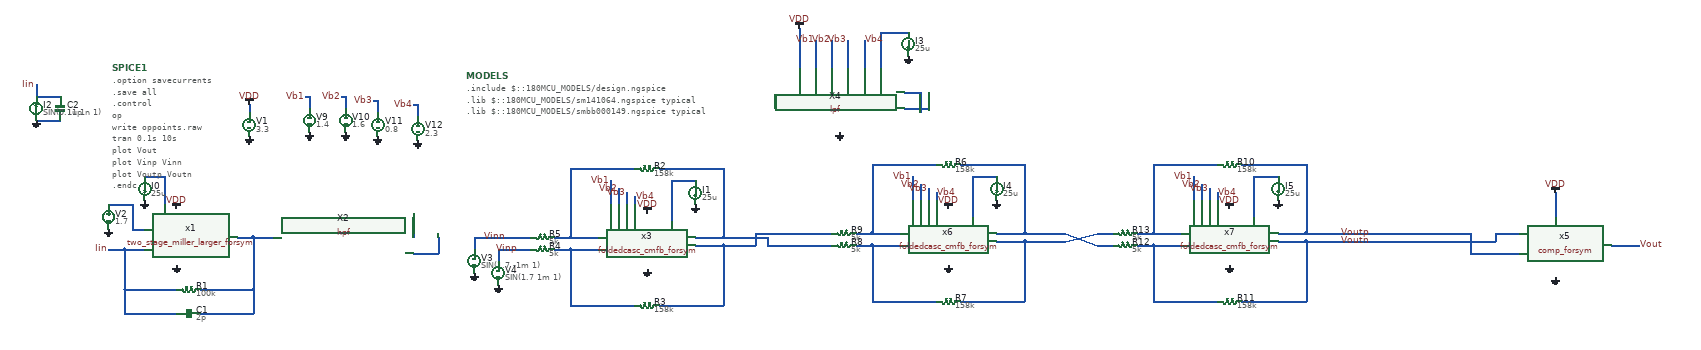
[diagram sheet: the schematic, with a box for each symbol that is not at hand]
v {xschem version=3.4.8RC file_version=1.3}
G {}
K {}
V {}
S {}
F {}
E {}
N -270 -240 -230 -240 {lab=#net1
spice_ignore=true}
N -500 -390 -450 -390 {lab=#net2
spice_ignore=true}
N -450 -390 -450 -320 {lab=#net2
spice_ignore=true}
N -230 -240 -230 -110 {lab=#net1
spice_ignore=true}
N -550 -210 -550 -110 {lab=Iin
spice_ignore=true}
N -550 -210 -500 -210 {lab=Iin
spice_ignore=true}
N -360 -110 -230 -110 {lab=#net1
spice_ignore=true}
N -550 -110 -420 -110 {lab=Iin
spice_ignore=true}
N -360 -50 -230 -50 {lab=#net1
spice_ignore=true}
N -230 -110 -230 -50 {lab=#net1
spice_ignore=true}
N -550 -50 -420 -50 {lab=Iin
spice_ignore=true}
N -550 -110 -550 -50 {lab=Iin
spice_ignore=true}
N -230 -240 -180 -240 {lab=#net1
spice_ignore=true}
N -590 -210 -550 -210 {lab=Iin
spice_ignore=true}
N -590 -320 -530 -320 {lab=#net3
spice_ignore=true}
N -530 -320 -530 -260 {lab=#net3
spice_ignore=true}
N -530 -260 -500 -260 {lab=#net3
spice_ignore=true}
N -240 -570 -240 -550 {lab=VDD}
N 870 -220 940 -220 {lab=#net1}
N 940 -220 940 -70 {lab=#net1}
N 560 -210 630 -210 {lab=#net2}
N 560 -240 630 -240 {lab=#net3}
N 560 -410 560 -260 {lab=#net3}
N 870 -240 940 -240 {lab=#net4}
N 940 -410 940 -240 {lab=#net4}
N 940 -240 1050 -240 {lab=#net4}
N 940 -220 1020 -220 {lab=#net1}
N 660 -380 660 -320 {lab=Vb1}
N 680 -360 680 -320 {lab=Vb2}
N 780 -410 940 -410 {lab=#net4}
N 560 -410 720 -410 {lab=#net3}
N 780 -70 940 -70 {lab=#net1}
N 560 -70 720 -70 {lab=#net2}
N 520 -240 560 -240 {lab=#net3}
N 520 -210 560 -210 {lab=#net2}
N 420 -210 460 -210 {lab=Vinp}
N 560 -260 560 -240 {lab=#net3}
N 560 -210 560 -70 {lab=#net2}
N 700 -350 700 -320 {lab=Vb3}
N 720 -340 720 -320 {lab=Vb4}
N 810 -380 810 -280 {lab=#net5}
N 810 -380 870 -380 {lab=#net5}
N -770 -620 -770 -590 {lab=Iin
spice_ignore=true}
N -770 -590 -710 -590 {lab=Iin
spice_ignore=true}
N -770 -530 -710 -530 {lab=0
spice_ignore=true}
N -90 -590 -90 -560 {lab=Vb1
}
N -100 -590 -90 -590 {lab=Vb1
}
N 0 -590 0 -560 {lab=Vb2
}
N -10 -590 0 -590 {lab=Vb2
}
N 80 -580 80 -550 {lab=Vb3
}
N 70 -580 80 -580 {lab=Vb3
}
N 180 -570 180 -540 {lab=Vb4
}
N 170 -570 180 -570 {lab=Vb4
}
N 1070 -580 1070 -560 {lab=#net6}
N 1130 -760 1130 -660 {lab=VDD}
N 1170 -730 1170 -660 {lab=Vb1}
N 1210 -730 1210 -660 {lab=Vb2}
N 1250 -730 1250 -660 {lab=Vb3}
N 1290 -730 1290 -660 {lab=Vb4}
N 1330 -750 1330 -660 {lab=#net7}
N 1330 -750 1400 -750 {lab=#net7}
N 170 -200 230 -200 {lab=#net13
spice_ignore=true}
N 230 -240 230 -200 {lab=#net13
spice_ignore=true}
N 170 -300 170 -240 {lab=#net14
spice_ignore=true}
N 420 -240 460 -240 {lab=Vinn}
N 320 -240 320 -210 {lab=Vinn
}
N 380 -210 380 -180 {lab=Vinp
}
N 380 -210 420 -210 {lab=Vinp}
N 320 -240 420 -240 {lab=Vinn}
N 3010 -350 3010 -290 {lab=VDD}
N 3150 -220 3220 -220 {lab=Vout}
N 1390 -560 1450 -560 {lab=#net8}
N 1450 -600 1450 -560 {lab=#net8}
N 2860 -250 2920 -250 {lab=Voutn}
N 1390 -600 1430 -600 {lab=#net9}
N 2840 -200 2920 -200 {lab=Voutp}
N 1430 -600 1430 -550 {lab=#net9}
N 2480 -250 2800 -250 {lab=Voutp}
N 2800 -250 2800 -200 {lab=Voutp}
N 2800 -200 2840 -200 {lab=Voutp}
N 2480 -230 2860 -230 {lab=Voutn}
N 2860 -250 2860 -230 {lab=Voutn}
N 1620 -230 1690 -230 {lab=#net10}
N 1690 -230 1690 -80 {lab=#net10}
N 1310 -220 1380 -220 {lab=#net11}
N 1310 -250 1380 -250 {lab=#net12}
N 1310 -420 1310 -270 {lab=#net12}
N 1620 -250 1690 -250 {lab=#net13}
N 1690 -420 1690 -250 {lab=#net13}
N 1690 -230 1770 -230 {lab=#net10}
N 1410 -390 1410 -330 {lab=Vb1}
N 1430 -370 1430 -330 {lab=Vb2}
N 1530 -420 1690 -420 {lab=#net13}
N 1310 -420 1470 -420 {lab=#net12}
N 1530 -80 1690 -80 {lab=#net10}
N 1310 -80 1470 -80 {lab=#net11}
N 1270 -250 1310 -250 {lab=#net12}
N 1270 -220 1310 -220 {lab=#net11}
N 1170 -220 1210 -220 {lab=#net4}
N 1310 -270 1310 -250 {lab=#net12}
N 1310 -220 1310 -80 {lab=#net11}
N 1450 -360 1450 -330 {lab=Vb3}
N 1470 -350 1470 -330 {lab=Vb4}
N 1560 -390 1560 -290 {lab=#net14}
N 1560 -390 1620 -390 {lab=#net14}
N 1170 -250 1210 -250 {lab=#net1}
N 1770 -230 1790 -230 {lab=#net10}
N 1690 -250 1790 -250 {lab=#net13}
N 1050 -240 1050 -220 {lab=#net4}
N 1050 -220 1170 -220 {lab=#net4}
N 1020 -250 1170 -250 {lab=#net1}
N 1020 -250 1020 -220 {lab=#net1}
N 2320 -230 2390 -230 {lab=Voutn}
N 2390 -230 2390 -80 {lab=Voutn}
N 2010 -220 2080 -220 {lab=#net15}
N 2010 -250 2080 -250 {lab=#net16}
N 2010 -420 2010 -270 {lab=#net16}
N 2320 -250 2390 -250 {lab=Voutp}
N 2390 -420 2390 -250 {lab=Voutp}
N 2390 -230 2470 -230 {lab=Voutn}
N 2110 -390 2110 -330 {lab=Vb1}
N 2130 -370 2130 -330 {lab=Vb2}
N 2230 -420 2390 -420 {lab=Voutp}
N 2010 -420 2170 -420 {lab=#net16}
N 2230 -80 2390 -80 {lab=Voutn}
N 2010 -80 2170 -80 {lab=#net15}
N 1970 -250 2010 -250 {lab=#net16}
N 1970 -220 2010 -220 {lab=#net15}
N 1870 -220 1910 -220 {lab=#net13}
N 2010 -270 2010 -250 {lab=#net16}
N 2010 -220 2010 -80 {lab=#net15}
N 2150 -360 2150 -330 {lab=Vb3}
N 2170 -350 2170 -330 {lab=Vb4}
N 2260 -390 2260 -290 {lab=#net17}
N 2260 -390 2320 -390 {lab=#net17}
N 1870 -250 1910 -250 {lab=#net10}
N 1790 -250 1870 -220 {lab=#net13}
N 1790 -230 1870 -250 {lab=#net10}
N 2390 -250 2480 -250 {lab=Voutp}
N 2470 -230 2480 -230 {lab=Voutn}
C {isource.sym} -500 -360 0 0 {name=I0 value=25u
spice_ignore=true}
C {gnd.sym} -500 -330 0 0 {name=l1 lab=0
spice_ignore=true}
C {vdd.sym} -420 -310 0 0 {name=l3 lab=VDD
spice_ignore=true}
C {gnd.sym} -420 -170 0 0 {name=l4 lab=0
spice_ignore=true}
C {vsource.sym} -240 -520 0 0 {name=V1 value=3.3 savecurrent=false}
C {vdd.sym} -240 -570 0 0 {name=l2 lab=VDD}
C {gnd.sym} -240 -490 0 0 {name=l11 lab=0}
C {lab_pin.sym} -590 -210 0 0 {name=p1 sig_type=std_logic lab=Iin
spice_ignore=true}
C {res.sym} -390 -110 1 0 {name=R1
value=100k
footprint=1206
device=resistor
m=1
spice_ignore=true}
C {capa.sym} -390 -50 1 0 {name=C1
m=1
value=2p
footprint=1206
device="ceramic capacitor"
spice_ignore=true}
C {gnd.sym} -590 -260 0 0 {name=l5 lab=0
spice_ignore=true}
C {vsource.sym} -590 -290 0 0 {name=V2 value=1.7 savecurrent=false
spice_ignore=true}
C {chipathon-2026-ppg/jz_tia/two_stage_miller_larger_forsym.sym} -420 -240 0 0 {name=x1
spice_ignore=true}
C {chipathon-2026-ppg/ps-filters/hpf.sym} 10 -220 0 0 {name=X2
spice_ignore=true}
C {lab_pin.sym} 680 -360 3 1 {name=p2 sig_type=std_logic lab=Vb2
}
C {lab_pin.sym} 660 -380 0 0 {name=p4 sig_type=std_logic lab=Vb1
}
C {vdd.sym} 750 -300 0 0 {name=l7 lab=VDD}
C {isource.sym} 870 -350 0 0 {name=I1 value=25u
}
C {gnd.sym} 750 -160 0 0 {name=l8 lab=0
}
C {res.sym} 750 -410 1 0 {name=R2
value=158k
footprint=1206
device=resistor
m=1}
C {res.sym} 750 -70 1 0 {name=R3
value=158k
footprint=1206
device=resistor
m=1}
C {res.sym} 490 -210 1 0 {name=R4
value=5k
footprint=1206
device=resistor
m=1}
C {res.sym} 490 -240 1 0 {name=R5
value=5k
footprint=1206
device=resistor
m=1}
C {chipathon-2026-ppg/jz_fda2/foldedcasc_cmfb_forsym.sym} 760 -30 0 0 {name=x3}
C {lab_pin.sym} 720 -340 0 1 {name=p7 sig_type=std_logic lab=Vb4
}
C {lab_pin.sym} 700 -350 3 1 {name=p8 sig_type=std_logic lab=Vb3
}
C {gnd.sym} 870 -320 0 0 {name=l9 lab=0
}
C {chipathon-2026-ppg/ps-filters/lpf.sym} 1230 -580 0 0 {name=X4}
C {gnd.sym} -770 -530 0 0 {name=l31 lab=0
spice_ignore=true}
C {lab_pin.sym} -770 -620 0 0 {name=p11 sig_type=std_logic lab=Iin
spice_ignore=true}
C {capa.sym} -710 -560 0 0 {name=C2
m=1
value=11p
footprint=1206
device="ceramic capacitor"
spice_ignore=true}
C {isource.sym} -770 -560 2 0 {name=I2 value="SIN(0.1u 1n 1)"
spice_ignore=true}
C {code_shown.sym} -580 -660 0 0 {name=SPICE1 only_toplevel=false value=".option savecurrents
.save all
.control
op
write oppoints.raw
tran 0.1s 10s
plot Vout
plot Vinp Vinn
plot Voutp Voutn
.endc"
}
C {vsource.sym} -90 -530 0 0 {name=V9 value=1.4 savecurrent=false
}
C {gnd.sym} -90 -500 0 0 {name=l14 lab=0
}
C {lab_pin.sym} -100 -590 0 0 {name=p14 sig_type=std_logic lab=Vb1
}
C {vsource.sym} 0 -530 0 0 {name=V10 value=1.6 savecurrent=false
}
C {gnd.sym} 0 -500 0 0 {name=l15 lab=0
}
C {lab_pin.sym} -10 -590 0 0 {name=p15 sig_type=std_logic lab=Vb2
}
C {vsource.sym} 80 -520 0 0 {name=V11 value=0.8 savecurrent=false
}
C {gnd.sym} 80 -490 0 0 {name=l16 lab=0
}
C {lab_pin.sym} 70 -580 0 0 {name=p16 sig_type=std_logic lab=Vb3
}
C {vsource.sym} 180 -510 0 0 {name=V12 value=2.3 savecurrent=false
}
C {gnd.sym} 180 -480 0 0 {name=l17 lab=0
}
C {lab_pin.sym} 170 -570 0 0 {name=p17 sig_type=std_logic lab=Vb4
}
C {gnd.sym} 1230 -500 0 0 {name=l6 lab=0
}
C {lab_pin.sym} 1170 -730 0 0 {name=p5 sig_type=std_logic lab=Vb1
}
C {lab_pin.sym} 1210 -730 3 1 {name=p6 sig_type=std_logic lab=Vb2
}
C {lab_pin.sym} 1250 -730 3 1 {name=p12 sig_type=std_logic lab=Vb3
}
C {lab_pin.sym} 1290 -730 0 1 {name=p13 sig_type=std_logic lab=Vb4
}
C {isource.sym} 1400 -720 0 0 {name=I3 value=25u
}
C {gnd.sym} 1400 -690 0 0 {name=l12 lab=0
}
C {vsource.sym} 320 -180 0 0 {name=V3 value="SIN(1.7 -1m 1)" savecurrent=false
}
C {gnd.sym} 320 -150 0 0 {name=l13 lab=0
}
C {vsource.sym} 380 -150 0 0 {name=V4 value="SIN(1.7 1m 1)" savecurrent=false
}
C {gnd.sym} 380 -120 0 0 {name=l18 lab=0
}
C {chipathon-2026-ppg/comparator/schematic-design/comp_forsym.sym} 3020 -220 0 0 {name=x5}
C {gnd.sym} 3010 -140 0 0 {name=l20 lab=0
}
C {lab_pin.sym} 3220 -220 0 1 {name=p3 sig_type=std_logic lab=Vout
}
C {vdd.sym} 1130 -760 0 0 {name=l10 lab=VDD}
C {vdd.sym} 3010 -350 0 0 {name=l19 lab=VDD}
C {code.sym} 300 -640 0 0 {name=MODELS only_toplevel=true  
format="tcleval( @value )" 
value="
.include $::180MCU_MODELS/design.ngspice
.lib $::180MCU_MODELS/sm141064.ngspice typical
.lib $::180MCU_MODELS/smbb000149.ngspice typical
"}
C {lab_pin.sym} 430 -210 1 1 {name=p9 sig_type=std_logic lab=Vinp
}
C {lab_pin.sym} 400 -240 3 1 {name=p10 sig_type=std_logic lab=Vinn
}
C {lab_pin.sym} 2550 -230 1 1 {name=p18 sig_type=std_logic lab=Voutn
}
C {lab_pin.sym} 2550 -250 3 1 {name=p19 sig_type=std_logic lab=Voutp
}
C {lab_pin.sym} 1430 -370 3 1 {name=p20 sig_type=std_logic lab=Vb2
}
C {lab_pin.sym} 1410 -390 0 0 {name=p21 sig_type=std_logic lab=Vb1
}
C {vdd.sym} 1500 -310 0 0 {name=l21 lab=VDD}
C {isource.sym} 1620 -360 0 0 {name=I4 value=25u
}
C {gnd.sym} 1500 -170 0 0 {name=l22 lab=0
}
C {res.sym} 1500 -420 1 0 {name=R6
value=158k
footprint=1206
device=resistor
m=1}
C {res.sym} 1500 -80 1 0 {name=R7
value=158k
footprint=1206
device=resistor
m=1}
C {res.sym} 1240 -220 1 0 {name=R8
value=5k
footprint=1206
device=resistor
m=1}
C {res.sym} 1240 -250 1 0 {name=R9
value=5k
footprint=1206
device=resistor
m=1}
C {chipathon-2026-ppg/jz_fda2/foldedcasc_cmfb_forsym.sym} 1510 -40 0 0 {name=x6}
C {lab_pin.sym} 1470 -350 0 1 {name=p22 sig_type=std_logic lab=Vb4
}
C {lab_pin.sym} 1450 -360 3 1 {name=p23 sig_type=std_logic lab=Vb3
}
C {gnd.sym} 1620 -330 0 0 {name=l23 lab=0
}
C {lab_pin.sym} 2130 -370 3 1 {name=p24 sig_type=std_logic lab=Vb2
}
C {lab_pin.sym} 2110 -390 0 0 {name=p25 sig_type=std_logic lab=Vb1
}
C {vdd.sym} 2200 -310 0 0 {name=l24 lab=VDD}
C {isource.sym} 2320 -360 0 0 {name=I5 value=25u
}
C {gnd.sym} 2200 -170 0 0 {name=l25 lab=0
}
C {res.sym} 2200 -420 1 0 {name=R10
value=158k
footprint=1206
device=resistor
m=1}
C {res.sym} 2200 -80 1 0 {name=R11
value=158k
footprint=1206
device=resistor
m=1}
C {res.sym} 1940 -220 1 0 {name=R12
value=5k
footprint=1206
device=resistor
m=1}
C {res.sym} 1940 -250 1 0 {name=R13
value=5k
footprint=1206
device=resistor
m=1}
C {chipathon-2026-ppg/jz_fda2/foldedcasc_cmfb_forsym.sym} 2210 -40 0 0 {name=x7}
C {lab_pin.sym} 2170 -350 0 1 {name=p26 sig_type=std_logic lab=Vb4
}
C {lab_pin.sym} 2150 -360 3 1 {name=p27 sig_type=std_logic lab=Vb3
}
C {gnd.sym} 2320 -330 0 0 {name=l26 lab=0
}
